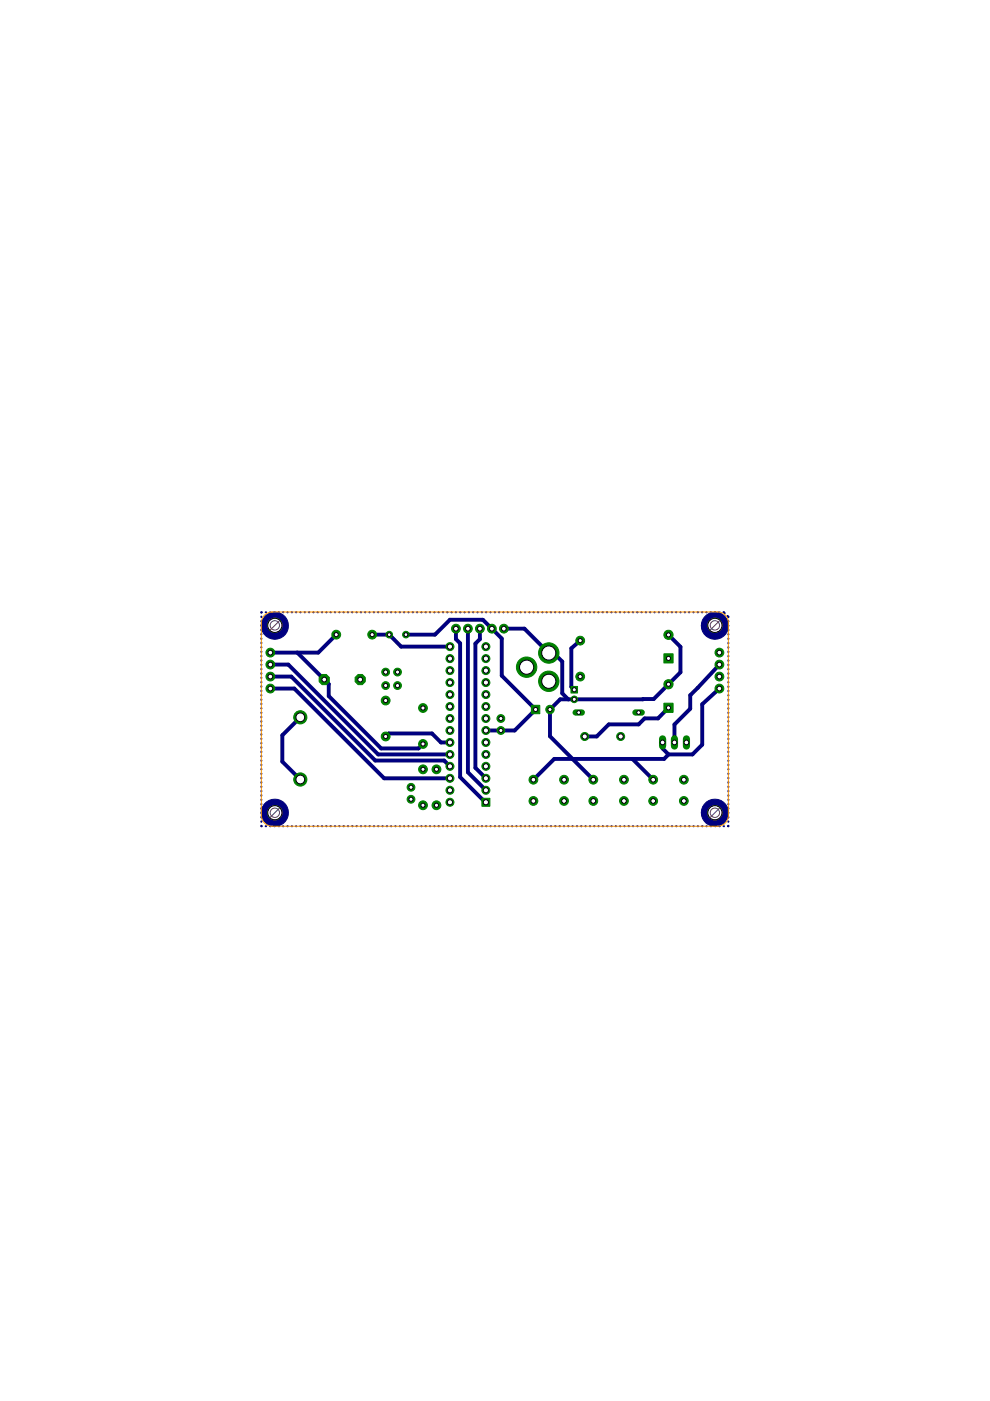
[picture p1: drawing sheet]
<svg xmlns="http://www.w3.org/2000/svg" width="210mm" height="297mm" viewBox="0 0 210 297" stroke-linecap="round" stroke-linejoin="round" font-family="sans-serif">
<g fill="#000080" stroke="#000080" stroke-width=".21">
<path d="M56 170.5a2.88 2.88 0 0 1 4.6 .2 2.88 2.88 0 0 1-1.5 4.3 2.88 2.88 0 0 1-3.7-2.7h2.5a.35 .35 0 0 1 .5-.4 .35 .35 0 0 1 .1 .6 .35 .35 0 0 1-.6-.1l-2.5-.1 .1-.6z" fill-rule="evenodd"/>
<path d="M56 130.9a2.89 2.89 0 0 1 4.7 .1 2.89 2.89 0 0 1-1.5 4.4 2.89 2.89 0 0 1-3.8-2.7h2.5a.35 .35 0 0 1 .5-.4 .35 .35 0 0 1 .1 .6 .35 .35 0 0 1-.6-.2h-2.5l.1-.7z" fill-rule="evenodd"/>
<path d="M149.3 130.9a2.88 2.88 0 0 1 4.7 .1 2.88 2.88 0 0 1-1.6 4.4 2.88 2.88 0 0 1-3.7-2.7h2.5a.35 .35 0 0 1 .6-.3 .35 .35 0 0 1 0 .6 .35 .35 0 0 1-.6-.3h-2.5l.3-1.3z" fill-rule="evenodd"/>
<path d="M149.8 170.1a2.89 2.89 0 0 1 4.4 .9 2.89 2.89 0 0 1-2 4.1 2.89 2.89 0 0 1-3.5-2.8h2.5a.35 .35 0 0 1 .6-.2 .35 .35 0 0 1 0 .6 .35 .35 0 0 1-.6-.3l-2.5-.1a2.87 2.87 0 0 1 1.1-2.2z" fill-rule="evenodd"/>
</g>
<g fill="none" stroke="#000080" stroke-width=".83">
<path d="M63 138.4l6.7 6.6v2.6l11.1 11.1h7.9l1-1M71.3 134.6l-3.8 3.8h-10.2M78.9 134.6h3.6l2.5 2.5h10.4M86.1 134.6h6.1l3.2-3.2h7l4 4v7.9l7.2 7.1-4.5 4.5h-6.1M96.7 133.3v2.2l.9 .9v28.4l5.4 5.3M99.2 133.3v30.4l3.8 3.9M101.7 133.3v2.2l-.9 1v26.3l2.2 2.2M106.8 133.3h4.4l5.2 5.2h1l1.8 1.8v6.7l1.3 1.3M123 135.8l-1.9 1.7v8.1l.7 .6M141.7 134.6l2.6 2.5v5.4l-5.7 5.7-19.8 .1-2.2 2.1v5.7l9.2 9.2M57.3 140.9h3.8l19.1 19.1h15.2M57.3 143.4h4.5l17.8 17.8h14.6l1.2 1.3"/>
<path d="M57.3 146h5.1l19 19h14M63.7 152.1l-3.8 3.8v5.6l3.8 3.8M81.8 156.1l.6-.6h9.2l1.9 1.9h1.9M140.5 157.4v1.3l1.2 1.3M141.7 144.7v.4M141.7 160l-.9 .9h-23.3l-4.4 4.4M141.7 150.1l-2.2 2.2h-2.8l-1.3 1.3h-6.3l-2.6 2.5h-2.5M152.5 146l-3.6 3.3v8.6l-2.1 2.1h-5.1M152.5 140.9l-6.2 6.5v2.9l-3.3 3.3v3.8M134.1 160.9l4.4 4.4"/>
</g>
<g fill="none" stroke="#000080" stroke-width=".42">
<path d="M55.4 130.7v.1M55.4 131.7v.1M55.4 132.6v.1M55.4 133.5v.1M55.4 134.4v.1M55.4 135.3v.2M55.4 136.3v.1M55.4 137.2v.1M55.4 138.1v.1M55.4 139v.1M55.4 140v.1M55.5 129.8l-.1 .1"/>
<path d="M56.3 129.8h.1M57.3 129.8h.1M58.2 129.8h.1M59.1 129.8h.1M60 129.8h.1M60.9 129.8h.1M61.8 129.8h.1M62.7 129.8h.1M63.6 129.8h.2M64.6 129.8h.1M65.5 129.8h.1M66.4 129.8h.1"/>
<path d="M67.3 129.8h.1M68.2 129.8h.1M69.2 129.8h.1M70.1 129.8h.1M71 129.8h.1M71.9 129.8h.1M72.8 129.8h.1M73.7 129.8h.1M74.6 129.8h.1M75.6 129.8h.1M76.5 129.8h.1M77.4 129.8h.1"/>
<path d="M78.3 129.8h.1M79.2 129.8h.1M80.1 129.8h.1M81 129.8h.2M82 129.8h.1M82.9 129.8h.1M83.8 129.8h.1M84.7 129.8h.1M85.6 129.8h.1M86.6 129.8h.1M87.5 129.8h.1M88.4 129.8h.1"/>
<path d="M89.3 129.8h.1M90.2 129.8h.1M91.1 129.8h.1M92 129.8h.1M93 129.8h.1M93.9 129.8h.1M94.8 129.8h.1M95.7 129.8h.1M96.6 129.8h.1M97.5 129.8h.1M98.4 129.8h.2M99.4 129.8h.1"/>
<path d="M100.3 129.8h.1M101.2 129.8h.1M102.1 129.8h.1M103 129.8h.1M103.9 129.8h.1M104.9 129.8h.1M105.8 129.8h.1M106.7 129.8h.1M107.6 129.8h.1M108.5 129.8h.1M109.4 129.8h.1M110.3 129.8h.1"/>
<path d="M111.3 129.8h.1M112.2 129.8h.1M113.1 129.8h.1M114 129.8h.1M114.9 129.8h.1M115.8 129.8h.2M116.8 129.8h.1M117.7 129.8h.1M118.6 129.8h.1M119.5 129.8h.1M120.4 129.8h.1M121.3 129.8h.1"/>
<path d="M122.3 129.8h.1M123.2 129.8h.1M124.1 129.8h.1M125 129.8h.1M125.9 129.8h.1M126.8 129.8h.1M127.7 129.8h.1M128.7 129.8h.1M129.6 129.8h.1M130.5 129.8h.1M131.4 129.8h.1M132.3 129.8h.1"/>
<path d="M133.2 129.8h.1M134.2 129.8h.1M135.1 129.8h.1M136 129.8h.1M136.9 129.8h.1M137.8 129.8h.1M138.7 129.8h.1M139.7 129.8h.1M140.6 129.8h.1M141.5 129.8h.1M142.4 129.8h.1M143.3 129.8h.1"/>
<path d="M144.2 129.8h.1M145.1 129.8h.1M146 129.8h.2M147 129.8h.1M147.9 129.8h.1M148.8 129.8h.1M149.7 129.8h.1M150.6 129.8h.1M151.6 129.8h.1M152.5 129.8h.1M153.4 129.8l.3 .2M154.2 130.6l.2 .3"/>
<path d="M154.4 131.7v.1M154.4 132.6v.1M154.4 133.5v.1M154.4 134.5v.1M154.4 135.4v.1M154.4 136.3v.1M154.4 137.2v.1M154.4 138.1v.2M154.4 139.1v.1M154.4 140v.1M55.4 140.9v.1M55.4 141.8v.1"/>
<path d="M55.4 142.7v.2M55.4 143.7v.1M55.4 144.6v.1M55.4 145.5v.1M55.4 146.4v.1M55.4 147.4v.1M55.4 148.3v.1M55.4 149.2v.1M55.4 150.1v.1M55.4 151v.2M55.4 152v.1M55.4 152.9v.1"/>
<path d="M55.4 153.8v.1M55.4 154.7v.2M55.4 155.7v.1M55.4 156.6v.1M55.4 157.5v.1M55.4 158.4v.2M55.4 159.4v.1M154.4 140.9v.1M154.4 141.8v.1M154.4 142.7v.2M154.4 143.7v.1M154.4 144.6v.1"/>
<path d="M154.4 145.5v.1M154.4 146.5v.1M154.4 147.4v.1M154.4 148.3v.1M154.4 149.2v.1M154.4 150.1v.2M154.4 151.1v.1M154.4 152v.1M154.4 152.9v.1M154.4 153.8v.1M154.4 154.7v.2M154.4 155.7v.1"/>
<path d="M154.4 156.6v.1M154.4 157.5v.1M154.4 158.5v.1M154.4 159.4v.1M55.4 160.3v.1M55.4 161.2v.1M55.4 162.1v.1M55.4 163v.2M55.4 164v.1M55.4 164.9v.1M55.4 165.8v.1M55.4 166.8v.1"/>
<path d="M55.4 167.7v.1M55.4 168.6v.1M55.4 169.5v.1M55.4 170.5v.1M55.4 171.4v.1M55.4 172.3v.1M55.4 173.2v.1M55.4 174.1v.1M55.4 175.1l.1 .1M56.3 175.2h.1M57.3 175.2h.1M58.2 175.2h.1"/>
<path d="M59.1 175.2h.1M60 175.2h.1M60.9 175.2h.1M61.8 175.2h.1M62.7 175.2h.1M63.6 175.2h.2M64.6 175.2h.1M65.5 175.2h.1M66.4 175.2h.1M67.3 175.2h.1M68.2 175.2h.1M69.2 175.2h.1"/>
<path d="M70.1 175.2h.1M71 175.2h.1M71.9 175.2h.1M72.8 175.2h.1M73.7 175.2h.1M74.7 175.2h.1M75.6 175.2h.1M76.5 175.2h.1M77.4 175.2h.1M78.3 175.2h.1M79.2 175.2h.1M80.1 175.2h.1"/>
<path d="M81.1 175.2h.1M82 175.2h.1M82.9 175.2h.1M83.8 175.2h.1M84.7 175.2h.1M85.6 175.2h.1M86.6 175.2h.1M87.5 175.2h.1M88.4 175.2h.1M89.3 175.2h.1M90.2 175.2h.1M91.1 175.2h.1"/>
<path d="M92.1 175.2h.1M93 175.2h.1M93.9 175.2h.1M94.8 175.2h.1M95.7 175.2h.1M96.6 175.2h.1M97.6 175.2h.1M98.5 175.2h.1M99.4 175.2h.1M100.3 175.2h.1M101.2 175.2h.1M102.1 175.2h.1"/>
<path d="M103 175.2h.1M103.9 175.2h.2M104.9 175.2h.1M105.8 175.2h.1M106.7 175.2h.1M107.6 175.2h.1M108.5 175.2h.1M109.5 175.2h.1M110.4 175.2h.1M111.3 175.2h.1M112.2 175.2h.1M113.1 175.2h.1"/>
<path d="M114 175.2h.1M115 175.2h.1M115.9 175.2h.1M116.8 175.2h.1M117.7 175.2h.1M118.6 175.2h.1M119.5 175.2h.1M120.4 175.2h.1M121.4 175.2h.1M122.3 175.2h.1M123.2 175.2h.1M124.1 175.2h.1"/>
<path d="M125 175.2h.1M125.9 175.2h.1M126.9 175.2h.1M127.8 175.2h.1M128.7 175.2h.1M129.6 175.2h.1M130.5 175.2h.1M131.4 175.2h.1M132.4 175.2h.1M133.3 175.2h.1M134.2 175.2h.1M135.1 175.2h.1"/>
<path d="M136 175.2h.1M136.9 175.2h.1M137.8 175.2h.1M138.8 175.2h.1M139.7 175.2h.1M140.6 175.2h.1M141.5 175.2h.1M142.4 175.2h.1M143.3 175.2h.1M144.3 175.2h.1M145.2 175.2h.1M146.1 175.2h.1"/>
<path d="M147 175.2h.1M147.9 175.2h.1M148.8 175.2h.1M149.8 175.2h.1M150.7 175.2h.1M151.6 175.2h.1M152.5 175.2h.1M153.4 175.2h.1M154.4 160.3v.1M154.4 161.2v.1M154.4 162.1v.1M154.4 163.1v.1"/>
<path d="M154.4 164v.1M154.4 164.9v.1M154.4 165.8v.1M154.4 166.8v.1M154.4 167.7v.1M154.4 168.6v.1M154.4 169.5v.1M154.4 170.5v.1M154.4 171.4v.1M154.4 172.3v.1M154.4 173.2v.1M154.4 174.1v.1"/>
<path d="M154.4 175.1l-.1 .1"/>
</g>
<circle cx="121.8" cy="148.3" r=".7" fill="#008000" stroke="#008000" stroke-width=".21"/>
<circle cx="121.8" cy="148.3" r=".44" fill="#fff" stroke="#000" stroke-width=".21"/>
<path d="M121.1 145.5h1.3v1.4h-1.3z" fill="#008000" stroke="#008000" stroke-width=".21"/>
<circle cx="121.8" cy="146.2" r=".44" fill="#fff" stroke="#000" stroke-width=".21"/>
<path d="M112.7 149.5h1.7v1.8h-1.7z" fill="#008000" stroke="#008000" stroke-width=".21"/>
<circle cx="113.6" cy="150.4" r=".44" fill="#fff" stroke="#000" stroke-width=".21"/>
<circle cx="116.6" cy="150.4" r=".89" fill="#008000" stroke="#008000" stroke-width=".21"/>
<circle cx="116.6" cy="150.4" r=".44" fill="#fff" stroke="#000" stroke-width=".21"/>
<circle cx="141.7" cy="145.1" r=".97" fill="#008000" stroke="#008000" stroke-width=".21"/>
<circle cx="141.7" cy="145.1" r=".44" fill="#fff" stroke="#000" stroke-width=".21"/>
<path d="M140.8 149.1h1.9v1.9h-1.9z" fill="#008000" stroke="#008000" stroke-width=".21"/>
<circle cx="141.7" cy="150.1" r=".44" fill="#fff" stroke="#000" stroke-width=".21"/>
<circle cx="141.7" cy="134.6" r=".97" fill="#008000" stroke="#008000" stroke-width=".21"/>
<circle cx="141.7" cy="134.6" r=".44" fill="#fff" stroke="#000" stroke-width=".21"/>
<path d="M140.8 138.6h1.9v2h-1.9z" fill="#008000" stroke="#008000" stroke-width=".21"/>
<circle cx="141.7" cy="139.6" r=".44" fill="#fff" stroke="#000" stroke-width=".21"/>
<circle cx="124" cy="156.1" r=".85" fill="#008000" stroke="#008000" stroke-width=".21"/>
<circle cx="124" cy="156.1" r=".55" fill="#fff" stroke="#000" stroke-width=".21"/>
<circle cx="131.6" cy="156.1" r=".85" fill="#008000" stroke="#008000" stroke-width=".21"/>
<circle cx="131.6" cy="156.1" r=".55" fill="#fff" stroke="#000" stroke-width=".21"/>
<path d="M134.7 151.1h1.4" fill="none" stroke="#008000" stroke-width="1.3"/>
<circle cx="135.4" cy="151.1" r=".4" fill="#fff" stroke="#000" stroke-width=".21"/>
<path d="M122 151.1h1.4" fill="none" stroke="#008000" stroke-width="1.3"/>
<circle cx="122.7" cy="151.1" r=".4" fill="#fff" stroke="#000" stroke-width=".21"/>
<circle cx="123" cy="135.8" r=".93" fill="#008000" stroke="#008000" stroke-width=".21"/>
<circle cx="123" cy="135.8" r=".44" fill="#fff" stroke="#000" stroke-width=".21"/>
<circle cx="123" cy="143.4" r=".93" fill="#008000" stroke="#008000" stroke-width=".21"/>
<circle cx="123" cy="143.4" r=".44" fill="#fff" stroke="#000" stroke-width=".21"/>
<circle cx="116.4" cy="144.4" r="2.16" fill="#008000" stroke="#008000" stroke-width=".21"/>
<circle cx="116.4" cy="144.4" r="1.5" fill="#fff" stroke="#000" stroke-width=".21"/>
<circle cx="116.4" cy="138.5" r="2.16" fill="#008000" stroke="#008000" stroke-width=".21"/>
<circle cx="116.4" cy="138.5" r="1.5" fill="#fff" stroke="#000" stroke-width=".21"/>
<circle cx="111.7" cy="141.5" r="2.16" fill="#008000" stroke="#008000" stroke-width=".21"/>
<circle cx="111.7" cy="141.5" r="1.5" fill="#fff" stroke="#000" stroke-width=".21"/>
<circle cx="152.5" cy="146" r=".93" fill="#008000" stroke="#008000" stroke-width=".21"/>
<circle cx="152.5" cy="146" r=".51" fill="#fff" stroke="#000" stroke-width=".21"/>
<circle cx="152.5" cy="143.4" r=".93" fill="#008000" stroke="#008000" stroke-width=".21"/>
<circle cx="152.5" cy="143.4" r=".51" fill="#fff" stroke="#000" stroke-width=".21"/>
<circle cx="152.5" cy="140.9" r=".93" fill="#008000" stroke="#008000" stroke-width=".21"/>
<circle cx="152.5" cy="140.9" r=".51" fill="#fff" stroke="#000" stroke-width=".21"/>
<circle cx="152.5" cy="138.4" r=".93" fill="#008000" stroke="#008000" stroke-width=".21"/>
<circle cx="152.5" cy="138.4" r=".51" fill="#fff" stroke="#000" stroke-width=".21"/>
<circle cx="57.3" cy="146" r=".93" fill="#008000" stroke="#008000" stroke-width=".21"/>
<circle cx="57.3" cy="146" r=".51" fill="#fff" stroke="#000" stroke-width=".21"/>
<circle cx="57.3" cy="143.4" r=".93" fill="#008000" stroke="#008000" stroke-width=".21"/>
<circle cx="57.3" cy="143.4" r=".51" fill="#fff" stroke="#000" stroke-width=".21"/>
<circle cx="57.3" cy="140.9" r=".93" fill="#008000" stroke="#008000" stroke-width=".21"/>
<circle cx="57.3" cy="140.9" r=".51" fill="#fff" stroke="#000" stroke-width=".21"/>
<circle cx="57.3" cy="138.4" r=".93" fill="#008000" stroke="#008000" stroke-width=".21"/>
<circle cx="57.3" cy="138.4" r=".51" fill="#fff" stroke="#000" stroke-width=".21"/>
<circle cx="86.1" cy="134.6" r=".7" fill="#008000" stroke="#008000" stroke-width=".21"/>
<circle cx="86.1" cy="134.6" r=".4" fill="#fff" stroke="#000" stroke-width=".21"/>
<circle cx="82.5" cy="134.6" r=".7" fill="#008000" stroke="#008000" stroke-width=".21"/>
<circle cx="82.5" cy="134.6" r=".4" fill="#fff" stroke="#000" stroke-width=".21"/>
<circle cx="71.3" cy="134.6" r=".93" fill="#008000" stroke="#008000" stroke-width=".21"/>
<circle cx="71.3" cy="134.6" r=".44" fill="#fff" stroke="#000" stroke-width=".21"/>
<circle cx="78.9" cy="134.6" r=".93" fill="#008000" stroke="#008000" stroke-width=".21"/>
<circle cx="78.9" cy="134.6" r=".44" fill="#fff" stroke="#000" stroke-width=".21"/>
<circle cx="125.8" cy="165.3" r=".93" fill="#008000" stroke="#008000" stroke-width=".21"/>
<circle cx="125.8" cy="165.3" r=".51" fill="#fff" stroke="#000" stroke-width=".21"/>
<circle cx="132.3" cy="165.3" r=".93" fill="#008000" stroke="#008000" stroke-width=".21"/>
<circle cx="132.3" cy="165.3" r=".51" fill="#fff" stroke="#000" stroke-width=".21"/>
<circle cx="125.8" cy="169.8" r=".93" fill="#008000" stroke="#008000" stroke-width=".21"/>
<circle cx="125.8" cy="169.8" r=".51" fill="#fff" stroke="#000" stroke-width=".21"/>
<circle cx="132.3" cy="169.8" r=".93" fill="#008000" stroke="#008000" stroke-width=".21"/>
<circle cx="132.3" cy="169.8" r=".51" fill="#fff" stroke="#000" stroke-width=".21"/>
<path d="M140.5 156.7v1.5" fill="none" stroke="#008000" stroke-width="1.5"/>
<circle cx="140.5" cy="157.4" r=".51" fill="#fff" stroke="#000" stroke-width=".21"/>
<path d="M143 156.7v1.5" fill="none" stroke="#008000" stroke-width="1.5"/>
<circle cx="143" cy="157.4" r=".51" fill="#fff" stroke="#000" stroke-width=".21"/>
<path d="M145.5 156.7v1.5" fill="none" stroke="#008000" stroke-width="1.5"/>
<circle cx="145.5" cy="157.4" r=".51" fill="#fff" stroke="#000" stroke-width=".21"/>
<circle cx="138.5" cy="165.3" r=".93" fill="#008000" stroke="#008000" stroke-width=".21"/>
<circle cx="138.5" cy="165.3" r=".51" fill="#fff" stroke="#000" stroke-width=".21"/>
<circle cx="145" cy="165.3" r=".93" fill="#008000" stroke="#008000" stroke-width=".21"/>
<circle cx="145" cy="165.3" r=".51" fill="#fff" stroke="#000" stroke-width=".21"/>
<circle cx="138.5" cy="169.8" r=".93" fill="#008000" stroke="#008000" stroke-width=".21"/>
<circle cx="138.5" cy="169.8" r=".51" fill="#fff" stroke="#000" stroke-width=".21"/>
<circle cx="145" cy="169.8" r=".93" fill="#008000" stroke="#008000" stroke-width=".21"/>
<circle cx="145" cy="169.8" r=".51" fill="#fff" stroke="#000" stroke-width=".21"/>
<circle cx="113.1" cy="165.3" r=".93" fill="#008000" stroke="#008000" stroke-width=".21"/>
<circle cx="113.1" cy="165.3" r=".51" fill="#fff" stroke="#000" stroke-width=".21"/>
<circle cx="119.6" cy="165.3" r=".93" fill="#008000" stroke="#008000" stroke-width=".21"/>
<circle cx="119.6" cy="165.3" r=".51" fill="#fff" stroke="#000" stroke-width=".21"/>
<circle cx="113.1" cy="169.8" r=".93" fill="#008000" stroke="#008000" stroke-width=".21"/>
<circle cx="113.1" cy="169.8" r=".51" fill="#fff" stroke="#000" stroke-width=".21"/>
<circle cx="119.6" cy="169.8" r=".93" fill="#008000" stroke="#008000" stroke-width=".21"/>
<circle cx="119.6" cy="169.8" r=".51" fill="#fff" stroke="#000" stroke-width=".21"/>
<circle cx="68.7" cy="144.1" r="1.17" fill="#008000" stroke="#008000" stroke-width=".21"/>
<circle cx="68.7" cy="144.1" r=".51" fill="#fff" stroke="#000" stroke-width=".21"/>
<circle cx="76.4" cy="144.1" r="1.17" fill="#008000" stroke="#008000" stroke-width=".21"/>
<circle cx="76.4" cy="144.1" r=".51" fill="#fff" stroke="#000" stroke-width=".21"/>
<circle cx="81.8" cy="148.5" r=".93" fill="#008000" stroke="#008000" stroke-width=".21"/>
<circle cx="81.8" cy="148.5" r=".44" fill="#fff" stroke="#000" stroke-width=".21"/>
<circle cx="81.8" cy="156.1" r=".93" fill="#008000" stroke="#008000" stroke-width=".21"/>
<circle cx="81.8" cy="156.1" r=".44" fill="#fff" stroke="#000" stroke-width=".21"/>
<path d="M102.2 169.2h1.7v1.7h-1.7z" fill="#008000" stroke="#008000" stroke-width=".21"/>
<circle cx="103" cy="170.1" r=".55" fill="#fff" stroke="#000" stroke-width=".21"/>
<circle cx="103" cy="167.6" r=".85" fill="#008000" stroke="#008000" stroke-width=".21"/>
<circle cx="103" cy="167.6" r=".55" fill="#fff" stroke="#000" stroke-width=".21"/>
<circle cx="103" cy="165" r=".85" fill="#008000" stroke="#008000" stroke-width=".21"/>
<circle cx="103" cy="165" r=".55" fill="#fff" stroke="#000" stroke-width=".21"/>
<circle cx="103" cy="162.5" r=".85" fill="#008000" stroke="#008000" stroke-width=".21"/>
<circle cx="103" cy="162.5" r=".55" fill="#fff" stroke="#000" stroke-width=".21"/>
<circle cx="103" cy="160" r=".85" fill="#008000" stroke="#008000" stroke-width=".21"/>
<circle cx="103" cy="160" r=".55" fill="#fff" stroke="#000" stroke-width=".21"/>
<circle cx="103" cy="157.4" r=".85" fill="#008000" stroke="#008000" stroke-width=".21"/>
<circle cx="103" cy="157.4" r=".55" fill="#fff" stroke="#000" stroke-width=".21"/>
<circle cx="103" cy="154.9" r=".85" fill="#008000" stroke="#008000" stroke-width=".21"/>
<circle cx="103" cy="154.9" r=".55" fill="#fff" stroke="#000" stroke-width=".21"/>
<circle cx="103" cy="152.3" r=".85" fill="#008000" stroke="#008000" stroke-width=".21"/>
<circle cx="103" cy="152.3" r=".55" fill="#fff" stroke="#000" stroke-width=".21"/>
<circle cx="103" cy="149.8" r=".85" fill="#008000" stroke="#008000" stroke-width=".21"/>
<circle cx="103" cy="149.8" r=".55" fill="#fff" stroke="#000" stroke-width=".21"/>
<circle cx="103" cy="147.3" r=".85" fill="#008000" stroke="#008000" stroke-width=".21"/>
<circle cx="103" cy="147.3" r=".55" fill="#fff" stroke="#000" stroke-width=".21"/>
<circle cx="103" cy="144.7" r=".85" fill="#008000" stroke="#008000" stroke-width=".21"/>
<circle cx="103" cy="144.7" r=".55" fill="#fff" stroke="#000" stroke-width=".21"/>
<circle cx="103" cy="142.2" r=".85" fill="#008000" stroke="#008000" stroke-width=".21"/>
<circle cx="103" cy="142.2" r=".55" fill="#fff" stroke="#000" stroke-width=".21"/>
<circle cx="103" cy="139.6" r=".85" fill="#008000" stroke="#008000" stroke-width=".21"/>
<circle cx="103" cy="139.6" r=".55" fill="#fff" stroke="#000" stroke-width=".21"/>
<circle cx="103" cy="137.1" r=".85" fill="#008000" stroke="#008000" stroke-width=".21"/>
<circle cx="103" cy="137.1" r=".55" fill="#fff" stroke="#000" stroke-width=".21"/>
<circle cx="95.4" cy="137.1" r=".85" fill="#008000" stroke="#008000" stroke-width=".21"/>
<circle cx="95.4" cy="137.1" r=".55" fill="#fff" stroke="#000" stroke-width=".21"/>
<circle cx="95.4" cy="139.6" r=".85" fill="#008000" stroke="#008000" stroke-width=".21"/>
<circle cx="95.4" cy="139.6" r=".55" fill="#fff" stroke="#000" stroke-width=".21"/>
<circle cx="95.4" cy="142.2" r=".85" fill="#008000" stroke="#008000" stroke-width=".21"/>
<circle cx="95.4" cy="142.2" r=".55" fill="#fff" stroke="#000" stroke-width=".21"/>
<circle cx="95.4" cy="144.7" r=".85" fill="#008000" stroke="#008000" stroke-width=".21"/>
<circle cx="95.4" cy="144.7" r=".55" fill="#fff" stroke="#000" stroke-width=".21"/>
<circle cx="95.4" cy="147.3" r=".85" fill="#008000" stroke="#008000" stroke-width=".21"/>
<circle cx="95.4" cy="147.3" r=".55" fill="#fff" stroke="#000" stroke-width=".21"/>
<circle cx="95.4" cy="149.8" r=".85" fill="#008000" stroke="#008000" stroke-width=".21"/>
<circle cx="95.4" cy="149.8" r=".55" fill="#fff" stroke="#000" stroke-width=".21"/>
<circle cx="95.4" cy="152.3" r=".85" fill="#008000" stroke="#008000" stroke-width=".21"/>
<circle cx="95.4" cy="152.3" r=".55" fill="#fff" stroke="#000" stroke-width=".21"/>
<circle cx="95.4" cy="154.9" r=".85" fill="#008000" stroke="#008000" stroke-width=".21"/>
<circle cx="95.4" cy="154.9" r=".55" fill="#fff" stroke="#000" stroke-width=".21"/>
<circle cx="95.4" cy="157.4" r=".85" fill="#008000" stroke="#008000" stroke-width=".21"/>
<circle cx="95.4" cy="157.4" r=".55" fill="#fff" stroke="#000" stroke-width=".21"/>
<circle cx="95.4" cy="160" r=".85" fill="#008000" stroke="#008000" stroke-width=".21"/>
<circle cx="95.4" cy="160" r=".55" fill="#fff" stroke="#000" stroke-width=".21"/>
<circle cx="95.4" cy="162.5" r=".85" fill="#008000" stroke="#008000" stroke-width=".21"/>
<circle cx="95.4" cy="162.5" r=".55" fill="#fff" stroke="#000" stroke-width=".21"/>
<circle cx="95.4" cy="165" r=".85" fill="#008000" stroke="#008000" stroke-width=".21"/>
<circle cx="95.4" cy="165" r=".55" fill="#fff" stroke="#000" stroke-width=".21"/>
<circle cx="95.4" cy="167.6" r=".85" fill="#008000" stroke="#008000" stroke-width=".21"/>
<circle cx="95.4" cy="167.6" r=".55" fill="#fff" stroke="#000" stroke-width=".21"/>
<circle cx="95.4" cy="170.1" r=".85" fill="#008000" stroke="#008000" stroke-width=".21"/>
<circle cx="95.4" cy="170.1" r=".55" fill="#fff" stroke="#000" stroke-width=".21"/>
<circle cx="63.7" cy="165.3" r="1.4" fill="#008000" stroke="#008000" stroke-width=".21"/>
<circle cx="63.7" cy="165.3" r=".93" fill="#fff" stroke="#000" stroke-width=".21"/>
<circle cx="63.7" cy="152.1" r="1.4" fill="#008000" stroke="#008000" stroke-width=".21"/>
<circle cx="63.7" cy="152.1" r=".93" fill="#fff" stroke="#000" stroke-width=".21"/>
<circle cx="106.8" cy="133.3" r=".93" fill="#008000" stroke="#008000" stroke-width=".21"/>
<circle cx="106.8" cy="133.3" r=".51" fill="#fff" stroke="#000" stroke-width=".21"/>
<circle cx="104.3" cy="133.3" r=".93" fill="#008000" stroke="#008000" stroke-width=".21"/>
<circle cx="104.3" cy="133.3" r=".51" fill="#fff" stroke="#000" stroke-width=".21"/>
<circle cx="101.7" cy="133.3" r=".93" fill="#008000" stroke="#008000" stroke-width=".21"/>
<circle cx="101.7" cy="133.3" r=".51" fill="#fff" stroke="#000" stroke-width=".21"/>
<circle cx="99.2" cy="133.3" r=".93" fill="#008000" stroke="#008000" stroke-width=".21"/>
<circle cx="99.2" cy="133.3" r=".51" fill="#fff" stroke="#000" stroke-width=".21"/>
<circle cx="96.7" cy="133.3" r=".93" fill="#008000" stroke="#008000" stroke-width=".21"/>
<circle cx="96.7" cy="133.3" r=".51" fill="#fff" stroke="#000" stroke-width=".21"/>
<circle cx="89.7" cy="157.7" r=".93" fill="#008000" stroke="#008000" stroke-width=".21"/>
<circle cx="89.7" cy="157.7" r=".44" fill="#fff" stroke="#000" stroke-width=".21"/>
<circle cx="89.7" cy="150.1" r=".93" fill="#008000" stroke="#008000" stroke-width=".21"/>
<circle cx="89.7" cy="150.1" r=".44" fill="#fff" stroke="#000" stroke-width=".21"/>
<circle cx="89.7" cy="170.7" r=".93" fill="#008000" stroke="#008000" stroke-width=".21"/>
<circle cx="89.7" cy="170.7" r=".44" fill="#fff" stroke="#000" stroke-width=".21"/>
<circle cx="89.7" cy="163.1" r=".93" fill="#008000" stroke="#008000" stroke-width=".21"/>
<circle cx="89.7" cy="163.1" r=".44" fill="#fff" stroke="#000" stroke-width=".21"/>
<circle cx="92.5" cy="163.1" r=".93" fill="#008000" stroke="#008000" stroke-width=".21"/>
<circle cx="92.5" cy="163.1" r=".44" fill="#fff" stroke="#000" stroke-width=".21"/>
<circle cx="92.5" cy="170.7" r=".93" fill="#008000" stroke="#008000" stroke-width=".21"/>
<circle cx="92.5" cy="170.7" r=".44" fill="#fff" stroke="#000" stroke-width=".21"/>
<circle cx="87.1" cy="166.9" r=".83" fill="#008000" stroke="#008000" stroke-width=".21"/>
<circle cx="87.1" cy="166.9" r=".44" fill="#fff" stroke="#000" stroke-width=".21"/>
<circle cx="87.1" cy="169.5" r=".83" fill="#008000" stroke="#008000" stroke-width=".21"/>
<circle cx="87.1" cy="169.5" r=".44" fill="#fff" stroke="#000" stroke-width=".21"/>
<circle cx="84.3" cy="145.4" r=".83" fill="#008000" stroke="#008000" stroke-width=".21"/>
<circle cx="84.3" cy="145.4" r=".44" fill="#fff" stroke="#000" stroke-width=".21"/>
<circle cx="81.8" cy="145.4" r=".83" fill="#008000" stroke="#008000" stroke-width=".21"/>
<circle cx="81.8" cy="145.4" r=".44" fill="#fff" stroke="#000" stroke-width=".21"/>
<circle cx="84.3" cy="142.5" r=".83" fill="#008000" stroke="#008000" stroke-width=".21"/>
<circle cx="84.3" cy="142.5" r=".44" fill="#fff" stroke="#000" stroke-width=".21"/>
<circle cx="81.8" cy="142.5" r=".83" fill="#008000" stroke="#008000" stroke-width=".21"/>
<circle cx="81.8" cy="142.5" r=".44" fill="#fff" stroke="#000" stroke-width=".21"/>
<circle cx="106.2" cy="152.3" r=".83" fill="#008000" stroke="#008000" stroke-width=".21"/>
<circle cx="106.2" cy="152.3" r=".44" fill="#fff" stroke="#000" stroke-width=".21"/>
<circle cx="106.2" cy="154.9" r=".83" fill="#008000" stroke="#008000" stroke-width=".21"/>
<circle cx="106.2" cy="154.9" r=".44" fill="#fff" stroke="#000" stroke-width=".21"/>
<g fill="none" stroke="#f90" stroke-width=".21">
<path d="M56.2 130.3l.7-.4 .8-.1h94.4a2.26 2.26 0 0 1 2.3 2.2v40.9a2.29 2.29 0 0 1-2.3 2.3h-94.4a2.29 2.29 0 0 1-2.3-2.3v-40.8l.1-.8z"/>
<circle cx="58.3" cy="172.3" r="1.5"/>
</g>
<circle cx="58.3" cy="172.3" r="1.5" fill="#fff" stroke="#000" stroke-width=".21"/>
<circle cx="58.3" cy="132.6" r="1.5" fill="none" stroke="#f90" stroke-width=".21"/>
<circle cx="58.3" cy="132.6" r="1.5" fill="#fff" stroke="#000" stroke-width=".21"/>
<circle cx="151.6" cy="132.6" r="1.5" fill="none" stroke="#f90" stroke-width=".21"/>
<circle cx="151.6" cy="132.6" r="1.5" fill="#fff" stroke="#000" stroke-width=".21"/>
<circle cx="151.6" cy="172.3" r="1.5" fill="none" stroke="#f90" stroke-width=".21"/>
<circle cx="151.6" cy="172.3" r="1.5" fill="#fff" stroke="#000" stroke-width=".21"/>
<g fill="none" stroke="#505050" stroke-width=".21">
<path d="M59.3 131.6l-2 2M152.6 131.6l-2 2M59.3 171.3l-2 2M152.6 171.3l-2 2"/>
<circle cx="58.3" cy="132.6" r=".99"/>
<circle cx="151.6" cy="132.6" r=".99"/>
<circle cx="58.3" cy="172.3" r=".99"/>
<circle cx="151.6" cy="172.3" r=".99"/>
</g>
</svg>
